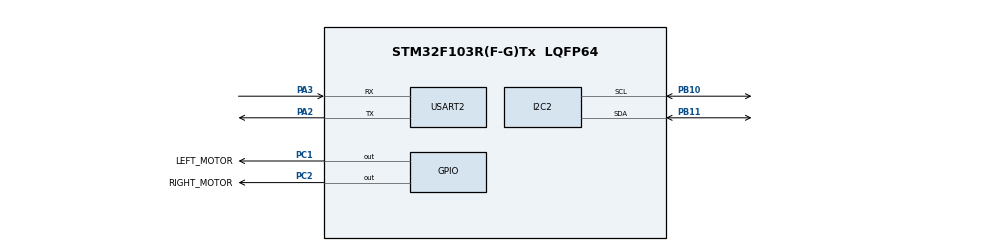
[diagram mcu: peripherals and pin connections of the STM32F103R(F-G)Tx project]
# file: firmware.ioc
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Mcu.Family=STM32F1
Mcu.Name=STM32F103R(F-G)Tx
Mcu.Package=LQFP64
NVIC.PriorityGroup=NVIC_PRIORITYGROUP_4
PA13.Mode=Serial_Wire
PA13.Signal=SYS_JTMS-SWDIO
PA14.Mode=Serial_Wire
PA14.Signal=SYS_JTCK-SWCLK
PA2.Mode=Asynchronous
PA2.Signal=USART2_TX
PA3.Mode=Asynchronous
PA3.Signal=USART2_RX
PB10.Mode=I2C
PB10.Signal=I2C2_SCL
PB11.Mode=I2C
PB11.Signal=I2C2_SDA
PC1.GPIO_Label=LEFT_MOTOR
PC1.Signal=GPIO_Output
PC2.GPIO_Label=RIGHT_MOTOR
PC2.Signal=GPIO_Output
PD0-OSC_IN.Mode=HSE-External-Oscillator
PD0-OSC_IN.Signal=RCC_OSC_IN
PD1-OSC_OUT.Mode=HSE-External-Oscillator
PD1-OSC_OUT.Signal=RCC_OSC_OUT
ProjectManager.HeapSize=0x200
ProjectManager.StackSize=0x400
ProjectManager.TargetToolchain=STM32CubeIDE
RCC.AHBFreq_Value=72000000
RCC.APB1CLKDivider=RCC_HCLK_DIV2
RCC.APB1Freq_Value=36000000
RCC.APB1TimFreq_Value=72000000
RCC.APB2Freq_Value=72000000
RCC.APB2TimFreq_Value=72000000
RCC.HCLKFreq_Value=72000000
RCC.PLLMUL=RCC_PLL_MUL9
RCC.PLLSourceVirtual=RCC_PLLSOURCE_HSE
RCC.SYSCLKFreq_VALUE=72000000
RCC.SYSCLKSource=RCC_SYSCLKSOURCE_PLLCLK
RCC.USBFreq_Value=72000000
USART2.VirtualMode=VM_ASYNC
board=custom

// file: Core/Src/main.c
/* USER CODE BEGIN Header */
/**
  ******************************************************************************
  * @file           : main.c
  * @brief          : Main program body
  ******************************************************************************
  * @attention
  *
  * Copyright (c) 2026 STMicroelectronics.
  * All rights reserved.
  *
  * This software is licensed under terms that can be found in the LICENSE file
  * in the root directory of this software component.
  * If no LICENSE file comes with this software, it is provided AS-IS.
  *
  ******************************************************************************
  */
/* USER CODE END Header */
#include "main.h"
#include "i2c.h"
#include "usart.h"
#include "gpio.h"

/* USER CODE BEGIN Includes */
#include "app_protocol.h"
#include "ble_link.h"
#include "board_config.h"
#include "console_diag.h"
#include "compass_lis3mdl.h"
#include "motor_control.h"
#include "navigation_controller.h"

#include <stdio.h>
#include <string.h>
/* USER CODE END Includes */

/* USER CODE BEGIN PV */
static char ble_line[BLE_LINE_BUFFER_SIZE];
static nav_command_t nav_command;
/* USER CODE END PV */

void SystemClock_Config(void);
/* USER CODE BEGIN PFP */
static void heartbeat_update(uint32_t now_ms);
#if BLE_LED_DEBUG
static void ble_tx_debug_update(uint32_t now_ms);
static void ble_baud_probe_update(uint32_t now_ms);
#endif
#if UART_TX_PROBE
static void uart_tx_probe_update(uint32_t now_ms);
#endif
#if PIN_TEST_MODE
static void run_pin_test_mode(void);
#endif
/* USER CODE END PFP */

/* USER CODE BEGIN 0 */
#if PIN_TEST_MODE
static void run_pin_test_mode(void) {
  GPIO_InitTypeDef gpio_init = {0};

  __HAL_RCC_GPIOA_CLK_ENABLE();

  /* PA2 (USART2_TX): force as plain GPIO output for multimeter UART test. */
  gpio_init.Pin = GPIO_PIN_2;
  gpio_init.Mode = GPIO_MODE_OUTPUT_PP;
  gpio_init.Pull = GPIO_NOPULL;
  gpio_init.Speed = GPIO_SPEED_FREQ_HIGH;
  HAL_GPIO_Init(GPIOA, &gpio_init);

  /* PA3 (USART2_RX): input with pull-up as a stable reference. */
  gpio_init.Pin = GPIO_PIN_3;
  gpio_init.Mode = GPIO_MODE_INPUT;
  gpio_init.Pull = GPIO_PULLUP;
  HAL_GPIO_Init(GPIOA, &gpio_init);

  gpio_init.Pin = LEFT_MOTOR_GPIO_PIN | RIGHT_MOTOR_GPIO_PIN;
  gpio_init.Mode = GPIO_MODE_OUTPUT_PP;
  gpio_init.Pull = GPIO_NOPULL;
  gpio_init.Speed = GPIO_SPEED_FREQ_HIGH;
  HAL_GPIO_Init(LEFT_MOTOR_GPIO_PORT, &gpio_init);

  HAL_GPIO_WritePin(LEFT_MOTOR_GPIO_PORT, LEFT_MOTOR_GPIO_PIN, LEFT_MOTOR_INACTIVE_STATE);
  HAL_GPIO_WritePin(RIGHT_MOTOR_GPIO_PORT, RIGHT_MOTOR_GPIO_PIN, RIGHT_MOTOR_INACTIVE_STATE);

  while (1) {
    /* Phase A: PA2 forced LOW (0V) for 4s. */
    HAL_GPIO_WritePin(GPIOA, GPIO_PIN_2, GPIO_PIN_RESET);
    HAL_GPIO_WritePin(LEFT_MOTOR_GPIO_PORT, LEFT_MOTOR_GPIO_PIN, LEFT_MOTOR_ACTIVE_STATE);
    HAL_GPIO_WritePin(RIGHT_MOTOR_GPIO_PORT, RIGHT_MOTOR_GPIO_PIN, RIGHT_MOTOR_INACTIVE_STATE);
    HAL_Delay(4000U);

    /* Phase B: PA2 forced HIGH (3.3V) for 4s. */
    HAL_GPIO_WritePin(GPIOA, GPIO_PIN_2, GPIO_PIN_SET);
    HAL_GPIO_WritePin(LEFT_MOTOR_GPIO_PORT, LEFT_MOTOR_GPIO_PIN, LEFT_MOTOR_INACTIVE_STATE);
    HAL_GPIO_WritePin(RIGHT_MOTOR_GPIO_PORT, RIGHT_MOTOR_GPIO_PIN, RIGHT_MOTOR_ACTIVE_STATE);
    HAL_Delay(4000U);
  }
}
#endif

static void heartbeat_update(uint32_t now_ms) {
#if !BLE_IDLE_HEARTBEAT
  (void)now_ms;
  return;
#else
  static uint8_t gpio_ready = 0U;
  GPIO_InitTypeDef gpio_init = {0};
  ble_link_status_t ble_status;
  uint32_t phase_ms = 0U;
  uint8_t left_on = 0U;
  uint8_t right_on = 0U;
  uint8_t rx_burst = 0U;

  if (motor_control_get_left_percent() != 0U || motor_control_get_right_percent() != 0U) {
    return;
  }

  if (gpio_ready == 0U) {
    gpio_init.Pin = LEFT_MOTOR_GPIO_PIN | RIGHT_MOTOR_GPIO_PIN;
    gpio_init.Mode = GPIO_MODE_OUTPUT_PP;
    gpio_init.Pull = GPIO_NOPULL;
    gpio_init.Speed = GPIO_SPEED_FREQ_HIGH;
    HAL_GPIO_Init(LEFT_MOTOR_GPIO_PORT, &gpio_init);
    gpio_ready = 1U;
  }

  ble_link_get_status(&ble_status);
  if (ble_status.state == BLE_LINK_STATE_TRANSPARENT &&
      (now_ms - ble_status.last_rx_tick_ms) < 120U) {
    rx_burst = 1U;
  }

  if (ble_status.state == BLE_LINK_STATE_TRANSPARENT) {
    if (rx_burst != 0U) {
      left_on = 1U;
      right_on = 1U;
    } else {
      phase_ms = now_ms % 1000U;
      left_on = 0U;
      right_on = (phase_ms < 140U) ? 1U : 0U;
    }
  } else {
    phase_ms = now_ms % 500U;
    left_on = (phase_ms < 250U) ? 1U : 0U;
    right_on = 0U;
  }

  HAL_GPIO_WritePin(LEFT_MOTOR_GPIO_PORT, LEFT_MOTOR_GPIO_PIN,
                    left_on ? LEFT_MOTOR_ACTIVE_STATE : LEFT_MOTOR_INACTIVE_STATE);
  HAL_GPIO_WritePin(RIGHT_MOTOR_GPIO_PORT, RIGHT_MOTOR_GPIO_PIN,
                    right_on ? RIGHT_MOTOR_ACTIVE_STATE : RIGHT_MOTOR_INACTIVE_STATE);
#endif
}

#if BLE_LED_DEBUG
static void ble_tx_debug_update(uint32_t now_ms) {
  static uint32_t last_ms = 0U;

  if ((now_ms - last_ms) < 1000U) {
    return;
  }
  last_ms = now_ms;
  ble_link_write("DBG tick\r\n");
}

static void ble_baud_probe_update(uint32_t now_ms) {
  static uint32_t last_switch_ms = 0U;
  static uint32_t last_announce_ms = 0U;
  ble_link_status_t ble_status;
  char line[48];

  ble_link_get_status(&ble_status);
  if ((now_ms - ble_status.last_rx_tick_ms) < 1500U) {
    return;
  }

  if ((now_ms - last_switch_ms) >= 2500U) {
    ble_link_debug_cycle_baud();
    last_switch_ms = now_ms;
    last_announce_ms = 0U;
  }

  if ((now_ms - last_announce_ms) >= 700U) {
    (void)snprintf(line, sizeof(line), "DBG baud=%lu\r\n", (unsigned long)ble_link_get_uart_baud());
    ble_link_write(line);
    last_announce_ms = now_ms;
  }
}
#endif

#if UART_TX_PROBE
static void uart_tx_probe_update(uint32_t now_ms) {
  static uint32_t last_ms = 0U;
  if ((now_ms - last_ms) < 1000U) {
    return;
  }
  last_ms = now_ms;
  ble_link_write("TX_MARK\r\n");
}
#endif

/* USER CODE END 0 */

int main(void)
{

  /* MCU Configuration--------------------------------------------------------*/

  /* Reset of all peripherals, Initializes the Flash interface and the Systick. */
  HAL_Init();

  /* Configure the system clock */
  SystemClock_Config();

  /* Initialize all configured peripherals */
  MX_GPIO_Init();
  MX_I2C2_Init();
  MX_USART2_UART_Init();
  /* USER CODE BEGIN 2 */
#if SMOKE_GREEN_BLINK_ONLY
  {
    GPIO_InitTypeDef gpio_init = {0};
    gpio_init.Pin = LEFT_MOTOR_GPIO_PIN | RIGHT_MOTOR_GPIO_PIN;
    gpio_init.Mode = GPIO_MODE_OUTPUT_PP;
    gpio_init.Pull = GPIO_NOPULL;
    gpio_init.Speed = GPIO_SPEED_FREQ_HIGH;
    HAL_GPIO_Init(RIGHT_MOTOR_GPIO_PORT, &gpio_init);

    HAL_GPIO_WritePin(LEFT_MOTOR_GPIO_PORT, LEFT_MOTOR_GPIO_PIN, LEFT_MOTOR_INACTIVE_STATE);
    HAL_GPIO_WritePin(RIGHT_MOTOR_GPIO_PORT, RIGHT_MOTOR_GPIO_PIN, RIGHT_MOTOR_INACTIVE_STATE);

    while (1) {
      /* LED test through the two former motor channels. */
      HAL_GPIO_WritePin(LEFT_MOTOR_GPIO_PORT, LEFT_MOTOR_GPIO_PIN, LEFT_MOTOR_ACTIVE_STATE);
      HAL_Delay(300U);
      HAL_GPIO_WritePin(LEFT_MOTOR_GPIO_PORT, LEFT_MOTOR_GPIO_PIN, LEFT_MOTOR_INACTIVE_STATE);
      HAL_Delay(300U);

      HAL_GPIO_WritePin(RIGHT_MOTOR_GPIO_PORT, RIGHT_MOTOR_GPIO_PIN, RIGHT_MOTOR_ACTIVE_STATE);
      HAL_Delay(300U);
      HAL_GPIO_WritePin(RIGHT_MOTOR_GPIO_PORT, RIGHT_MOTOR_GPIO_PIN, RIGHT_MOTOR_INACTIVE_STATE);
      HAL_Delay(300U);

      HAL_GPIO_WritePin(LEFT_MOTOR_GPIO_PORT, LEFT_MOTOR_GPIO_PIN, LEFT_MOTOR_ACTIVE_STATE);
      HAL_GPIO_WritePin(RIGHT_MOTOR_GPIO_PORT, RIGHT_MOTOR_GPIO_PIN, RIGHT_MOTOR_ACTIVE_STATE);
      HAL_Delay(500U);
      HAL_GPIO_WritePin(LEFT_MOTOR_GPIO_PORT, LEFT_MOTOR_GPIO_PIN, LEFT_MOTOR_INACTIVE_STATE);
      HAL_GPIO_WritePin(RIGHT_MOTOR_GPIO_PORT, RIGHT_MOTOR_GPIO_PIN, RIGHT_MOTOR_INACTIVE_STATE);
      HAL_Delay(700U);
    }
  }
#endif
#if PIN_TEST_MODE
  run_pin_test_mode();
#endif
  motor_control_init();
  navigation_controller_init();
  compass_lis3mdl_init();
  ble_link_init();
  console_diag_init();
  /* USER CODE END 2 */

  /* Infinite loop */
  while (1)
  {

    /* USER CODE BEGIN 3 */
    ble_link_poll_uart();

    if (ble_link_poll_line(ble_line, sizeof(ble_line))) {
      if (console_diag_try_handle(ble_line)) {
        /* handled by console */
      } else if (app_protocol_parse_line(ble_line, &nav_command)) {
        navigation_controller_handle_command(&nav_command);
      } else {
        console_diag_printf("unknown command: %s\r\n", ble_line);
        console_diag_print_prompt();
      }
      memset(ble_line, 0, sizeof(ble_line));
    }

    console_diag_update(HAL_GetTick());
    navigation_controller_update(HAL_GetTick());
    motor_control_update(HAL_GetTick());
    heartbeat_update(HAL_GetTick());
#if BLE_LED_DEBUG
    ble_tx_debug_update(HAL_GetTick());
    ble_baud_probe_update(HAL_GetTick());
#endif
#if UART_TX_PROBE
    uart_tx_probe_update(HAL_GetTick());
#endif
  }
  /* USER CODE END 3 */
}

void SystemClock_Config(void)
{
  RCC_OscInitTypeDef RCC_OscInitStruct = {0};
  RCC_ClkInitTypeDef RCC_ClkInitStruct = {0};

  /* HSI-only clock tree: do not use external crystal at all. */
  RCC_OscInitStruct.OscillatorType = RCC_OSCILLATORTYPE_HSI;
  RCC_OscInitStruct.HSIState = RCC_HSI_ON;
  RCC_OscInitStruct.HSICalibrationValue = RCC_HSICALIBRATION_DEFAULT;
  RCC_OscInitStruct.HSEState = RCC_HSE_OFF;
  RCC_OscInitStruct.PLL.PLLState = RCC_PLL_ON;
  RCC_OscInitStruct.PLL.PLLSource = RCC_PLLSOURCE_HSI_DIV2;
  RCC_OscInitStruct.PLL.PLLMUL = RCC_PLL_MUL16; /* 8MHz/2 * 16 = 64MHz */
  if (HAL_RCC_OscConfig(&RCC_OscInitStruct) != HAL_OK)
  {
    Error_Handler();
  }

  RCC_ClkInitStruct.ClockType = RCC_CLOCKTYPE_HCLK|RCC_CLOCKTYPE_SYSCLK
                              |RCC_CLOCKTYPE_PCLK1|RCC_CLOCKTYPE_PCLK2;
  RCC_ClkInitStruct.SYSCLKSource = RCC_SYSCLKSOURCE_PLLCLK;
  RCC_ClkInitStruct.AHBCLKDivider = RCC_SYSCLK_DIV1;
  RCC_ClkInitStruct.APB1CLKDivider = RCC_HCLK_DIV2; /* <=36MHz on APB1 */
  RCC_ClkInitStruct.APB2CLKDivider = RCC_HCLK_DIV1;
  if (HAL_RCC_ClockConfig(&RCC_ClkInitStruct, FLASH_LATENCY_2) != HAL_OK)
  {
    Error_Handler();
  }
}

void Error_Handler(void)
{
  /* USER CODE BEGIN Error_Handler_Debug */
  GPIO_InitTypeDef gpio_init = {0};
  volatile uint32_t wait = 0U;

  __disable_irq();
  __HAL_RCC_GPIOC_CLK_ENABLE();
  gpio_init.Pin = LEFT_MOTOR_GPIO_PIN | RIGHT_MOTOR_GPIO_PIN;
  gpio_init.Mode = GPIO_MODE_OUTPUT_PP;
  gpio_init.Pull = GPIO_NOPULL;
  gpio_init.Speed = GPIO_SPEED_FREQ_LOW;
  HAL_GPIO_Init(LEFT_MOTOR_GPIO_PORT, &gpio_init);

  while (1)
  {
    HAL_GPIO_TogglePin(LEFT_MOTOR_GPIO_PORT, LEFT_MOTOR_GPIO_PIN);
    HAL_GPIO_TogglePin(RIGHT_MOTOR_GPIO_PORT, RIGHT_MOTOR_GPIO_PIN);
    for (wait = 0U; wait < 250000U; ++wait) {
      __NOP();
    }
  }
  /* USER CODE END Error_Handler_Debug */
}
